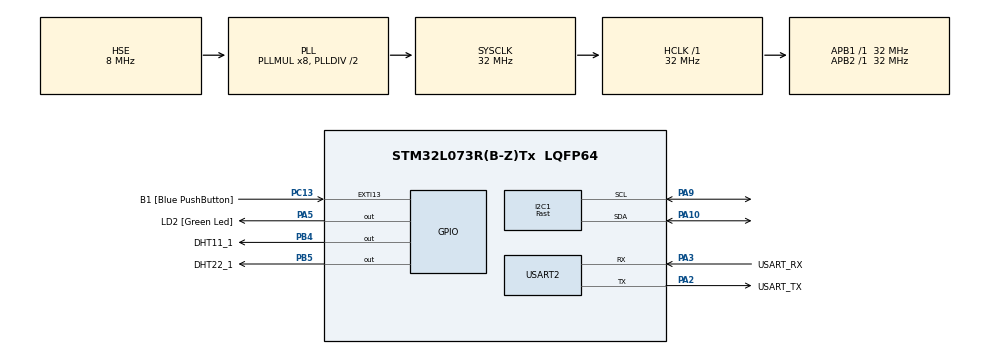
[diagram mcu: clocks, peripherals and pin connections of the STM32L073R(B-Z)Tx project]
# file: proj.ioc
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I2C1.I2C_Speed_Mode=I2C_Fast
I2C1.Timing=0x00300F38
Mcu.Family=STM32L0
Mcu.Name=STM32L073R(B-Z)Tx
Mcu.Package=LQFP64
PA10.Mode=I2C
PA10.Signal=I2C1_SDA
PA13.GPIO_Label=TMS
PA13.Mode=Serial_Wire
PA13.Signal=SYS_SWDIO
PA14.GPIO_Label=TCK
PA14.Mode=Serial_Wire
PA14.Signal=SYS_SWCLK
PA2.GPIO_Label=USART_TX
PA2.Mode=Asynchronous
PA2.Signal=USART2_TX
PA3.GPIO_Label=USART_RX
PA3.Mode=Asynchronous
PA3.Signal=USART2_RX
PA5.GPIO_Label=LD2 [Green Led]
PA5.Signal=GPIO_Output
PA9.Mode=I2C
PA9.Signal=I2C1_SCL
PB4.GPIO_Label=DHT11_1
PB4.Signal=GPIO_Output
PB5.GPIO_Label=DHT22_1
PB5.Signal=GPIO_Output
PC13.GPIO_Label=B1 [Blue PushButton]
PC13.GPIO_ModeDefaultEXTI=GPIO_MODE_IT_FALLING
PC13.Signal=GPXTI13
PC14-OSC32_IN.Mode=LSE-External-Oscillator
PC14-OSC32_IN.Signal=RCC_OSC32_IN
PC15-OSC32_OUT.Mode=LSE-External-Oscillator
PC15-OSC32_OUT.Signal=RCC_OSC32_OUT
PH0-OSC_IN.GPIO_Label=MCO
PH0-OSC_IN.Mode=HSE-External-Clock-Source
PH0-OSC_IN.Signal=RCC_OSC_IN
ProjectManager.HeapSize=0x200
ProjectManager.StackSize=0x400
ProjectManager.TargetToolchain=STM32CubeIDE
RCC.AHBFreq_Value=32000000
RCC.APB1Freq_Value=32000000
RCC.APB1TimFreq_Value=32000000
RCC.APB2Freq_Value=32000000
RCC.APB2TimFreq_Value=32000000
RCC.HCLKFreq_Value=32000000
RCC.HSE_VALUE=8000000
RCC.HSI16_VALUE=16000000
RCC.HSI48_VALUE=48000000
RCC.HSI_VALUE=16000000
RCC.MSI_VALUE=2097000
RCC.PLLMUL=RCC_PLLMUL_8
RCC.PLLSourceVirtual=RCC_PLLSOURCE_HSE
RCC.SYSCLKFreq_VALUE=32000000
RCC.SYSCLKSource=RCC_SYSCLKSOURCE_PLLCLK
RCC.VCOOutputFreq_Value=64000000
USART2.VirtualMode-Asynchronous=VM_ASYNC
board=NUCLEO-L073RZ

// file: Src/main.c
/* USER CODE BEGIN Header */
/**
  ******************************************************************************
  * @file           : main.c
  * @brief          : Main program body
  ******************************************************************************
  * @attention
  *
  * Copyright (c) 2024 STMicroelectronics.
  * All rights reserved.
  *
  * This software is licensed under terms that can be found in the LICENSE file
  * in the root directory of this software component.
  * If no LICENSE file comes with this software, it is provided AS-IS.
  *
  ******************************************************************************
  */
/* USER CODE END Header */
#include "main.h"

/* USER CODE BEGIN Includes */
#include "ssd1306.h"
#include "ssd1306_fonts.h"
#include "ssd1306_tests.h"
/* USER CODE END Includes */

I2C_HandleTypeDef hi2c1;

UART_HandleTypeDef huart2;

void SystemClock_Config(void);
static void MX_GPIO_Init(void);
static void MX_USART2_UART_Init(void);
static void MX_I2C1_Init(void);

/* USER CODE BEGIN 0 */

/* DEFINE THE DHT DataTypedef
* Look in the DHT.h for the definition
*/
DHT_DataTypedef DHT11_Data;
uint8_t Temperature, Humidity;
uint8_t Humidity2;

/* USER CODE END 0 */

int main(void)
{

  /* MCU Configuration--------------------------------------------------------*/

  /* Reset of all peripherals, Initializes the Flash interface and the Systick. */
  HAL_Init();

  /* Configure the system clock */
  SystemClock_Config();

  /* Initialize all configured peripherals */
  MX_GPIO_Init();
  MX_USART2_UART_Init();
  MX_I2C1_Init();
  /* USER CODE BEGIN 2 */
ssd1306_Init();
  /* USER CODE END 2 */
uint8_t a = 0;
uint8_t Acnt = 4;
uint8_t Bcnt = 0;
uint8_t ar [] = {38, 38, 37, 38, 37, 37, 37};
uint8_t br [] = {1, 2, 2, 1, 2, 2, 3};
  /* Infinite loop */
  while (1)
  {

	  HAL_Delay(1900);
	  HAL_GPIO_TogglePin(LD2_GPIO_Port,LD2_Pin);
	  HAL_Delay(100);
	  HAL_GPIO_TogglePin(LD2_GPIO_Port,LD2_Pin);
	  Acnt++;
	  ssd1306_Fill(Black);
      ssd1306_SetCursor(2, 0);
      char buf[64];
      sprintf(buf, "VID:%d%% \n\r", ar[a]);
      ssd1306_WriteString(buf, Font_16x15, White);
   	  HAL_UART_Transmit(&huart2, buf, 11, 10);
      ssd1306_SetCursor(2, 15);
      sprintf(buf, "DIF:%d%% \n\n\r", br[a]);
      ssd1306_WriteString(buf, Font_16x15, White);
   	  HAL_UART_Transmit(&huart2, buf, 11, 10);

   	  if (Acnt == 5){
	  Bcnt++;
	  ssd1306_UpdateScreen();
	  Acnt = 0;
	  }

   	  if (Bcnt == 10){

   	  DHT_GetData(&DHT11_Data);

   	  Humidity = DHT11_Data.Humidity;

   	  HAL_GPIO_TogglePin(GPIOA, GPIO_PIN_6);
	  HAL_Delay(2000);
	  HAL_GPIO_TogglePin(GPIOA, GPIO_PIN_6);
	  a++;
   	  Bcnt = 0;
   	  }

      if (a == 7){
    	  a = 0;
      }

  }
}

void SystemClock_Config(void)
{
  RCC_OscInitTypeDef RCC_OscInitStruct = {0};
  RCC_ClkInitTypeDef RCC_ClkInitStruct = {0};
  RCC_PeriphCLKInitTypeDef PeriphClkInit = {0};

  /** Configure the main internal regulator output voltage
  */
  __HAL_PWR_VOLTAGESCALING_CONFIG(PWR_REGULATOR_VOLTAGE_SCALE1);

  /** Initializes the RCC Oscillators according to the specified parameters
  * in the RCC_OscInitTypeDef structure.
  */
  RCC_OscInitStruct.OscillatorType = RCC_OSCILLATORTYPE_HSE;
  RCC_OscInitStruct.HSEState = RCC_HSE_BYPASS;
  RCC_OscInitStruct.PLL.PLLState = RCC_PLL_ON;
  RCC_OscInitStruct.PLL.PLLSource = RCC_PLLSOURCE_HSE;
  RCC_OscInitStruct.PLL.PLLMUL = RCC_PLLMUL_8;
  RCC_OscInitStruct.PLL.PLLDIV = RCC_PLLDIV_2;
  if (HAL_RCC_OscConfig(&RCC_OscInitStruct) != HAL_OK)
  {
    Error_Handler();
  }

  /** Initializes the CPU, AHB and APB buses clocks
  */
  RCC_ClkInitStruct.ClockType = RCC_CLOCKTYPE_HCLK|RCC_CLOCKTYPE_SYSCLK
                              |RCC_CLOCKTYPE_PCLK1|RCC_CLOCKTYPE_PCLK2;
  RCC_ClkInitStruct.SYSCLKSource = RCC_SYSCLKSOURCE_PLLCLK;
  RCC_ClkInitStruct.AHBCLKDivider = RCC_SYSCLK_DIV1;
  RCC_ClkInitStruct.APB1CLKDivider = RCC_HCLK_DIV1;
  RCC_ClkInitStruct.APB2CLKDivider = RCC_HCLK_DIV1;

  if (HAL_RCC_ClockConfig(&RCC_ClkInitStruct, FLASH_LATENCY_1) != HAL_OK)
  {
    Error_Handler();
  }
  PeriphClkInit.PeriphClockSelection = RCC_PERIPHCLK_USART2|RCC_PERIPHCLK_I2C1;
  PeriphClkInit.Usart2ClockSelection = RCC_USART2CLKSOURCE_PCLK1;
  PeriphClkInit.I2c1ClockSelection = RCC_I2C1CLKSOURCE_PCLK1;
  if (HAL_RCCEx_PeriphCLKConfig(&PeriphClkInit) != HAL_OK)
  {
    Error_Handler();
  }
}

static void MX_I2C1_Init(void)
{

  hi2c1.Instance = I2C1;
  hi2c1.Init.Timing = 0x00300F38;
  hi2c1.Init.OwnAddress1 = 0;
  hi2c1.Init.AddressingMode = I2C_ADDRESSINGMODE_7BIT;
  hi2c1.Init.DualAddressMode = I2C_DUALADDRESS_DISABLE;
  hi2c1.Init.OwnAddress2 = 0;
  hi2c1.Init.OwnAddress2Masks = I2C_OA2_NOMASK;
  hi2c1.Init.GeneralCallMode = I2C_GENERALCALL_DISABLE;
  hi2c1.Init.NoStretchMode = I2C_NOSTRETCH_DISABLE;
  if (HAL_I2C_Init(&hi2c1) != HAL_OK)
  {
    Error_Handler();
  }

  /** Configure Analogue filter
  */
  if (HAL_I2CEx_ConfigAnalogFilter(&hi2c1, I2C_ANALOGFILTER_ENABLE) != HAL_OK)
  {
    Error_Handler();
  }

  /** Configure Digital filter
  */
  if (HAL_I2CEx_ConfigDigitalFilter(&hi2c1, 0) != HAL_OK)
  {
    Error_Handler();
  }

}

static void MX_USART2_UART_Init(void)
{

  huart2.Instance = USART2;
  huart2.Init.BaudRate = 115200;
  huart2.Init.WordLength = UART_WORDLENGTH_8B;
  huart2.Init.StopBits = UART_STOPBITS_1;
  huart2.Init.Parity = UART_PARITY_NONE;
  huart2.Init.Mode = UART_MODE_TX_RX;
  huart2.Init.HwFlowCtl = UART_HWCONTROL_NONE;
  huart2.Init.OverSampling = UART_OVERSAMPLING_16;
  huart2.Init.OneBitSampling = UART_ONE_BIT_SAMPLE_DISABLE;
  huart2.AdvancedInit.AdvFeatureInit = UART_ADVFEATURE_NO_INIT;
  if (HAL_UART_Init(&huart2) != HAL_OK)
  {
    Error_Handler();
  }

}

static void MX_GPIO_Init(void)
{
  GPIO_InitTypeDef GPIO_InitStruct = {0};

  /* GPIO Ports Clock Enable */
  __HAL_RCC_GPIOC_CLK_ENABLE();
  __HAL_RCC_GPIOH_CLK_ENABLE();
  __HAL_RCC_GPIOA_CLK_ENABLE();

  /*Configure GPIO pin Output Level */
  HAL_GPIO_WritePin(GPIOA, GPIO_PIN_1|LD2_Pin|GPIO_PIN_6, GPIO_PIN_RESET);

  /*Configure GPIO pin : B1_Pin */
  GPIO_InitStruct.Pin = B1_Pin;
  GPIO_InitStruct.Mode = GPIO_MODE_IT_FALLING;
  GPIO_InitStruct.Pull = GPIO_NOPULL;
  HAL_GPIO_Init(B1_GPIO_Port, &GPIO_InitStruct);

  /*Configure GPIO pins : PA1 LD2_Pin PA6 */
  GPIO_InitStruct.Pin = GPIO_PIN_1|LD2_Pin|GPIO_PIN_6;
  GPIO_InitStruct.Mode = GPIO_MODE_OUTPUT_PP;
  GPIO_InitStruct.Pull = GPIO_NOPULL;
  GPIO_InitStruct.Speed = GPIO_SPEED_FREQ_LOW;
  HAL_GPIO_Init(GPIOA, &GPIO_InitStruct);

}

void Error_Handler(void)
{
  __disable_irq();
  while (1)
  {
  }
}
